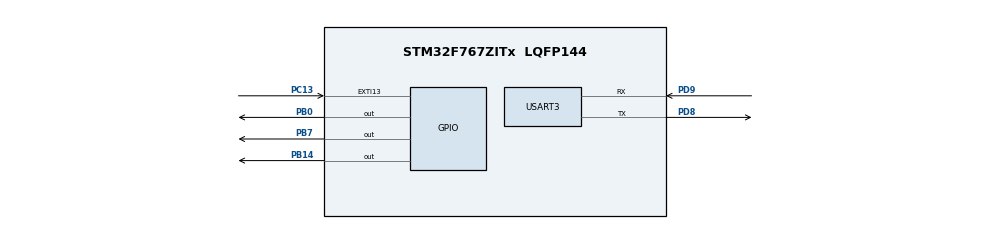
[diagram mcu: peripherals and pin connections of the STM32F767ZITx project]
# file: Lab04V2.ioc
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Mcu.Family=STM32F7
Mcu.Name=STM32F767ZITx
Mcu.Package=LQFP144
NVIC.EXTI15_10_IRQn=true\:1\:3\:true\:false\:true\:true\:true
NVIC.PriorityGroup=NVIC_PRIORITYGROUP_1
PB0.Signal=GPIO_Output
PB14.Signal=GPIO_Output
PB7.Signal=GPIO_Output
PC13.Signal=GPXTI13
PD8.Mode=Asynchronous
PD8.Signal=USART3_TX
PD9.Mode=Asynchronous
PD9.Signal=USART3_RX
ProjectManager.HeapSize=0x200
ProjectManager.StackSize=0x400
ProjectManager.TargetToolchain=STM32CubeIDE
RCC.AHBFreq_Value=216000000
RCC.APB1CLKDivider=RCC_HCLK_DIV4
RCC.APB1Freq_Value=54000000
RCC.APB1TimFreq_Value=108000000
RCC.APB2CLKDivider=RCC_HCLK_DIV2
RCC.APB2Freq_Value=108000000
RCC.APB2TimFreq_Value=216000000
RCC.CortexFreq_Value=216000000
RCC.HCLKFreq_Value=216000000
RCC.HSE_VALUE=25000000
RCC.HSI_VALUE=16000000
RCC.LSE_VALUE=32768
RCC.PLLM=8
RCC.PLLN=216
RCC.SYSCLKFreq_VALUE=216000000
RCC.SYSCLKSource=RCC_SYSCLKSOURCE_PLLCLK
RCC.USBFreq_Value=216000000
RCC.VCOOutputFreq_Value=432000000
USART3.VirtualMode-Asynchronous=VM_ASYNC
board=custom

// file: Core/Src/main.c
/* USER CODE BEGIN Header */
/**
  ******************************************************************************
  * @file           : main.c
  * @brief          : Main program body
  ******************************************************************************
  * @attention
  *
  * <h2><center>&copy; Copyright (c) 2021 STMicroelectronics.
  * All rights reserved.</center></h2>
  *
  * This software component is licensed by ST under BSD 3-Clause license,
  * the "License"; You may not use this file except in compliance with the
  * License. You may obtain a copy of the License at:
  *                        opensource.org/licenses/BSD-3-Clause
  *
  ******************************************************************************
  */
/* USER CODE END Header */
#include "main.h"
#include "usart.h"
#include "gpio.h"

void SystemClock_Config(void);

int main(void)
{

  /* MCU Configuration--------------------------------------------------------*/

  /* Reset of all peripherals, Initializes the Flash interface and the Systick. */
  HAL_Init();

  /* Configure the system clock */
  SystemClock_Config();

  /* Initialize all configured peripherals */
  MX_GPIO_Init();
  MX_USART3_UART_Init();

  /* Infinite loop */
  while (1)
  {

    /* USER CODE BEGIN 3 */
	  HAL_UART_Transmit(&huart3, (uint8_t *) ".", 1, 100);
	  HAL_Delay(400);
  }
  /* USER CODE END 3 */
}

void SystemClock_Config(void)
{
  RCC_OscInitTypeDef RCC_OscInitStruct = {0};
  RCC_ClkInitTypeDef RCC_ClkInitStruct = {0};

  /** Configure the main internal regulator output voltage
  */
  __HAL_RCC_PWR_CLK_ENABLE();
  __HAL_PWR_VOLTAGESCALING_CONFIG(PWR_REGULATOR_VOLTAGE_SCALE1);
  /** Initializes the RCC Oscillators according to the specified parameters
  * in the RCC_OscInitTypeDef structure.
  */
  RCC_OscInitStruct.OscillatorType = RCC_OSCILLATORTYPE_HSI;
  RCC_OscInitStruct.HSIState = RCC_HSI_ON;
  RCC_OscInitStruct.HSICalibrationValue = RCC_HSICALIBRATION_DEFAULT;
  RCC_OscInitStruct.PLL.PLLState = RCC_PLL_ON;
  RCC_OscInitStruct.PLL.PLLSource = RCC_PLLSOURCE_HSI;
  RCC_OscInitStruct.PLL.PLLM = 8;
  RCC_OscInitStruct.PLL.PLLN = 180;
  RCC_OscInitStruct.PLL.PLLP = RCC_PLLP_DIV2;
  RCC_OscInitStruct.PLL.PLLQ = 4;
  if (HAL_RCC_OscConfig(&RCC_OscInitStruct) != HAL_OK)
  {
    Error_Handler();
  }
  /** Activate the Over-Drive mode
  */
  if (HAL_PWREx_EnableOverDrive() != HAL_OK)
  {
    Error_Handler();
  }
  /** Initializes the CPU, AHB and APB buses clocks
  */
  RCC_ClkInitStruct.ClockType = RCC_CLOCKTYPE_HCLK|RCC_CLOCKTYPE_SYSCLK
                              |RCC_CLOCKTYPE_PCLK1|RCC_CLOCKTYPE_PCLK2;
  RCC_ClkInitStruct.SYSCLKSource = RCC_SYSCLKSOURCE_PLLCLK;
  RCC_ClkInitStruct.AHBCLKDivider = RCC_SYSCLK_DIV1;
  RCC_ClkInitStruct.APB1CLKDivider = RCC_HCLK_DIV4;
  RCC_ClkInitStruct.APB2CLKDivider = RCC_HCLK_DIV2;

  if (HAL_RCC_ClockConfig(&RCC_ClkInitStruct, FLASH_LATENCY_5) != HAL_OK)
  {
    Error_Handler();
  }
}

/* USER CODE BEGIN 4 */
void HAL_GPIO_EXTI_Callback(uint16_t GPIO_Pin){
	//NO 1
	if(GPIO_Pin == GPIO_PIN_13){
		HAL_UART_Transmit(&huart3, (uint8_t *) "---", 3, 100);
		HAL_Delay(200);
		for(int i=0; i<20; i++)
		{
		HAL_UART_Transmit(&huart3, (uint8_t *) "B", 1, 100);
		HAL_Delay(200);
		}
	}
	//NO 2
	else if(GPIO_Pin == GPIO_PIN_0){
		HAL_UART_Transmit(&huart3, (uint8_t *) "---", 3, 100);
		HAL_Delay(200);
		for(int i=0; i<20; i++)
		{
		HAL_UART_Transmit(&huart3, (uint8_t *) "E", 1, 100);
		HAL_Delay(200);
		}
	}

}

/* USER CODE END 4 */

void HAL_TIM_PeriodElapsedCallback(I2C_HandleTypeDef *htim)
{
  if (htim->Instance == TIM1) {
    HAL_IncTick();
  }
}

void Error_Handler(void)
{
  __disable_irq();
  while (1)
  {
  }
}

/************************ (C) COPYRIGHT STMicroelectronics *****END OF FILE****/
